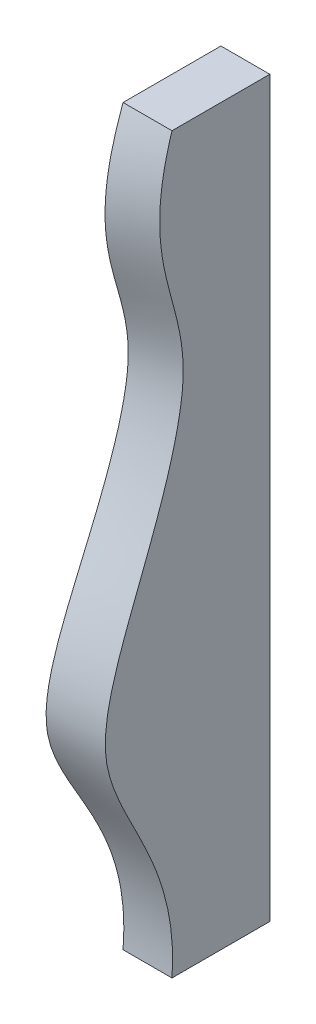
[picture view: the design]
ISO-10303-21;
HEADER;
FILE_DESCRIPTION(('STEP AP214'),'2;1');
FILE_NAME('part.step','',(''),(''),'','','');
FILE_SCHEMA(('AUTOMOTIVE_DESIGN { 1 0 10303 214 1 1 1 1 }'));
ENDSEC;
DATA;
#1=APPLICATION_CONTEXT('core data for automotive mechanical design processes');
#2=APPLICATION_PROTOCOL_DEFINITION('international standard','automotive_design',2000,#1);
#3=PRODUCT_CONTEXT('',#1,'mechanical');
#4=PRODUCT('Part','Part','',(#3));
#5=PRODUCT_RELATED_PRODUCT_CATEGORY('part','',(#4));
#6=PRODUCT_DEFINITION_FORMATION('','',#4);
#7=PRODUCT_DEFINITION_CONTEXT('part definition',#1,'design');
#8=PRODUCT_DEFINITION('design','',#6,#7);
#9=PRODUCT_DEFINITION_SHAPE('','',#8);
#10=(LENGTH_UNIT() NAMED_UNIT(*) SI_UNIT(.MILLI.,.METRE.));
#11=(NAMED_UNIT(*) PLANE_ANGLE_UNIT() SI_UNIT($,.RADIAN.));
#12=(NAMED_UNIT(*) SI_UNIT($,.STERADIAN.) SOLID_ANGLE_UNIT());
#13=UNCERTAINTY_MEASURE_WITH_UNIT(LENGTH_MEASURE(1.E-05),#10,'distance_accuracy_value','');
#14=(GEOMETRIC_REPRESENTATION_CONTEXT(3) GLOBAL_UNCERTAINTY_ASSIGNED_CONTEXT((#13)) GLOBAL_UNIT_ASSIGNED_CONTEXT((#10,
#11,#12)) REPRESENTATION_CONTEXT('',''));
#15=CARTESIAN_POINT('',(0.,0.,0.));
#16=DIRECTION('',(0.,0.,1.));
#17=DIRECTION('',(1.,0.,0.));
#18=AXIS2_PLACEMENT_3D('',#15,#16,#17);
#19=CARTESIAN_POINT('',(450.,375.,253.120113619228));
#20=DIRECTION('',(1.,0.,0.));
#21=DIRECTION('',(0.,0.,-1.));
#22=AXIS2_PLACEMENT_3D('',#19,#20,#21);
#23=PLANE('',#22);
#24=CARTESIAN_POINT('',(450.,375.,100.));
#25=CARTESIAN_POINT('',(450.,373.034518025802,100.617893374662));
#26=CARTESIAN_POINT('',(450.,371.063498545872,101.218327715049));
#27=CARTESIAN_POINT('',(450.,367.106931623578,102.38292904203));
#28=CARTESIAN_POINT('',(450.,365.121364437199,102.947028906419));
#29=CARTESIAN_POINT('',(450.,361.136834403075,104.036051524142));
#30=CARTESIAN_POINT('',(450.,359.137857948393,104.560924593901));
#31=CARTESIAN_POINT('',(450.,355.127662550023,105.568528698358));
#32=CARTESIAN_POINT('',(450.,353.116435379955,106.051227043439));
#33=CARTESIAN_POINT('',(450.,349.082885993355,106.971524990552));
#34=CARTESIAN_POINT('',(450.,347.060559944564,107.409107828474));
#35=CARTESIAN_POINT('',(450.,343.005968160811,108.236239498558));
#36=CARTESIAN_POINT('',(450.,340.973701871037,108.625785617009));
#37=CARTESIAN_POINT('',(450.,336.925879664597,109.349411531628));
#38=CARTESIAN_POINT('',(450.,334.910438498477,109.684131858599));
#39=CARTESIAN_POINT('',(450.,330.872251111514,110.301237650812));
#40=CARTESIAN_POINT('',(450.,328.849507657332,110.583641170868));
#41=CARTESIAN_POINT('',(450.,324.797929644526,111.093589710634));
#42=CARTESIAN_POINT('',(450.,322.769097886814,111.321156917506));
#43=CARTESIAN_POINT('',(450.,318.706578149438,111.719126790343));
#44=CARTESIAN_POINT('',(450.,316.672892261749,111.889550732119));
#45=CARTESIAN_POINT('',(450.,312.601936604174,112.171223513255));
#46=CARTESIAN_POINT('',(450.,310.564667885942,112.2824875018));
#47=CARTESIAN_POINT('',(450.,306.487835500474,112.444211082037));
#48=CARTESIAN_POINT('',(450.,304.44827200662,112.494674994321));
#49=CARTESIAN_POINT('',(450.,300.766861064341,112.529866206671));
#50=CARTESIAN_POINT('',(450.,299.125109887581,112.525504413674));
#51=CARTESIAN_POINT('',(450.,295.841944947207,112.476390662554));
#52=CARTESIAN_POINT('',(450.,294.20053127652,112.431632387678));
#53=CARTESIAN_POINT('',(450.,290.9191510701,112.301744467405));
#54=CARTESIAN_POINT('',(450.,289.279184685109,112.216611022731));
#55=CARTESIAN_POINT('',(450.,286.0017716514,112.006369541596));
#56=CARTESIAN_POINT('',(450.,284.364325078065,111.881260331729));
#57=CARTESIAN_POINT('',(450.,281.093002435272,111.591875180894));
#58=CARTESIAN_POINT('',(450.,279.459126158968,111.427601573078));
#59=CARTESIAN_POINT('',(450.,276.195965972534,111.061140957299));
#60=CARTESIAN_POINT('',(450.,274.566681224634,110.858961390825));
#61=CARTESIAN_POINT('',(450.,271.308912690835,110.417766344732));
#62=CARTESIAN_POINT('',(450.,269.680441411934,110.178658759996));
#63=CARTESIAN_POINT('',(450.,266.429067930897,109.66611714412));
#64=CARTESIAN_POINT('',(450.,264.806165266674,109.39268603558));
#65=CARTESIAN_POINT('',(450.,261.565975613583,108.814016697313));
#66=CARTESIAN_POINT('',(450.,259.948688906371,108.508776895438));
#67=CARTESIAN_POINT('',(450.,256.719693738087,107.869432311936));
#68=CARTESIAN_POINT('',(450.,255.107985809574,107.535324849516));
#69=CARTESIAN_POINT('',(450.,251.890031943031,106.84158166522));
#70=CARTESIAN_POINT('',(450.,250.283786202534,106.481945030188));
#71=CARTESIAN_POINT('',(450.,247.076559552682,105.740892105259));
#72=CARTESIAN_POINT('',(450.,245.475578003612,105.359478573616));
#73=CARTESIAN_POINT('',(450.,241.50463574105,104.389998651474));
#74=CARTESIAN_POINT('',(450.,239.137299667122,103.791213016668));
#75=CARTESIAN_POINT('',(450.,234.409562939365,102.56858360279));
#76=CARTESIAN_POINT('',(450.,232.049161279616,101.944743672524));
#77=CARTESIAN_POINT('',(450.,227.330957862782,100.687056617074));
#78=CARTESIAN_POINT('',(450.,224.97315619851,100.053209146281));
#79=CARTESIAN_POINT('',(450.,220.255645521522,98.7912632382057));
#80=CARTESIAN_POINT('',(450.,217.895936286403,98.1631656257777));
#81=CARTESIAN_POINT('',(450.,213.180890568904,96.9316236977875));
#82=CARTESIAN_POINT('',(450.,210.825579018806,96.3280848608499));
#83=CARTESIAN_POINT('',(450.,206.105641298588,95.1587191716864));
#84=CARTESIAN_POINT('',(450.,203.74101552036,94.5928907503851));
#85=CARTESIAN_POINT('',(450.,198.999701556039,93.5143370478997));
#86=CARTESIAN_POINT('',(450.,196.623014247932,93.0016079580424));
#87=CARTESIAN_POINT('',(450.,193.047444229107,92.2829932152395));
#88=CARTESIAN_POINT('',(450.,191.853625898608,92.0518328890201));
#89=CARTESIAN_POINT('',(450.,189.462562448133,91.6080101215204));
#90=CARTESIAN_POINT('',(450.,188.265317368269,91.395347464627));
#91=CARTESIAN_POINT('',(450.,185.438603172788,90.9175979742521));
#92=CARTESIAN_POINT('',(450.,183.807693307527,90.6609641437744));
#93=CARTESIAN_POINT('',(450.,180.539482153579,90.188070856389));
#94=CARTESIAN_POINT('',(450.,178.902178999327,89.9718242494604));
#95=CARTESIAN_POINT('',(450.,175.622465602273,89.582792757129));
#96=CARTESIAN_POINT('',(450.,173.980055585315,89.4100059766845));
#97=CARTESIAN_POINT('',(450.,170.691479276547,89.1103508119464));
#98=CARTESIAN_POINT('',(450.,169.045314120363,88.9834700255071));
#99=CARTESIAN_POINT('',(450.,165.7506468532,88.7774420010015));
#100=CARTESIAN_POINT('',(450.,164.10214592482,88.698275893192));
#101=CARTESIAN_POINT('',(450.,160.804237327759,88.5888757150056));
#102=CARTESIAN_POINT('',(450.,159.154830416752,88.5586193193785));
#103=CARTESIAN_POINT('',(450.,156.67780275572,88.5503605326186));
#104=CARTESIAN_POINT('',(450.,155.850205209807,88.5538336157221));
#105=CARTESIAN_POINT('',(450.,154.195150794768,88.5732733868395));
#106=CARTESIAN_POINT('',(450.,153.3676939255,88.5892400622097));
#107=CARTESIAN_POINT('',(450.,151.71303295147,88.6336548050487));
#108=CARTESIAN_POINT('',(450.,150.885828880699,88.6621041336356));
#109=CARTESIAN_POINT('',(450.,149.231947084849,88.7315153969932));
#110=CARTESIAN_POINT('',(450.,148.405269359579,88.7724773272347));
#111=CARTESIAN_POINT('',(450.,146.752342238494,88.8663764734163));
#112=CARTESIAN_POINT('',(450.,145.926093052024,88.9193173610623));
#113=CARTESIAN_POINT('',(450.,144.274400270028,89.0364829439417));
#114=CARTESIAN_POINT('',(450.,143.448956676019,89.1007076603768));
#115=CARTESIAN_POINT('',(450.,140.973367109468,89.3094573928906));
#116=CARTESIAN_POINT('',(450.,139.32455581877,89.4700233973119));
#117=CARTESIAN_POINT('',(450.,136.030767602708,89.8296137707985));
#118=CARTESIAN_POINT('',(450.,134.385791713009,90.0286475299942));
#119=CARTESIAN_POINT('',(450.,131.921842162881,90.353227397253));
#120=CARTESIAN_POINT('',(450.,131.101130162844,90.4657560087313));
#121=CARTESIAN_POINT('',(450.,129.46087288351,90.6990804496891));
#122=CARTESIAN_POINT('',(450.,128.641327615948,90.8198763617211));
#123=CARTESIAN_POINT('',(450.,126.487607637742,91.147902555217));
#124=CARTESIAN_POINT('',(450.,125.154422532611,91.3616516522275));
#125=CARTESIAN_POINT('',(450.,122.491297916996,91.8085097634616));
#126=CARTESIAN_POINT('',(450.,121.161358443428,92.0416189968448));
#127=CARTESIAN_POINT('',(450.,118.504649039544,92.5258118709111));
#128=CARTESIAN_POINT('',(450.,117.177879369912,92.7768969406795));
#129=CARTESIAN_POINT('',(450.,114.527649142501,93.2958707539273));
#130=CARTESIAN_POINT('',(450.,113.204188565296,93.5637593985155));
#131=CARTESIAN_POINT('',(450.,109.238311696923,94.3911977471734));
#132=CARTESIAN_POINT('',(450.,106.600813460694,94.974443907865));
#133=CARTESIAN_POINT('',(450.,101.338948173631,96.1967655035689));
#134=CARTESIAN_POINT('',(450.,98.7145807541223,96.8358393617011));
#135=CARTESIAN_POINT('',(450.,93.4750061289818,98.1644316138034));
#136=CARTESIAN_POINT('',(450.,90.8598154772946,98.8540151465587));
#137=CARTESIAN_POINT('',(450.,85.6414988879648,100.277365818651));
#138=CARTESIAN_POINT('',(450.,83.0383730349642,101.011133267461));
#139=CARTESIAN_POINT('',(450.,77.8401683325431,102.518956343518));
#140=CARTESIAN_POINT('',(450.,75.2451043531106,103.293063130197));
#141=CARTESIAN_POINT('',(450.,70.0657152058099,104.876319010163));
#142=CARTESIAN_POINT('',(450.,67.4813900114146,105.68546801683));
#143=CARTESIAN_POINT('',(450.,62.3209633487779,107.335422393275));
#144=CARTESIAN_POINT('',(450.,59.7448685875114,108.176248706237));
#145=CARTESIAN_POINT('',(450.,54.6018401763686,109.8854300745));
#146=CARTESIAN_POINT('',(450.,52.0349065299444,110.753785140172));
#147=CARTESIAN_POINT('',(450.,46.9102618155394,112.514359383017));
#148=CARTESIAN_POINT('',(450.,44.3525478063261,113.406570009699));
#149=CARTESIAN_POINT('',(450.,39.2445395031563,115.21200108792));
#150=CARTESIAN_POINT('',(450.,36.6942452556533,116.125221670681));
#151=CARTESIAN_POINT('',(450.,28.9927594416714,118.913724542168));
#152=CARTESIAN_POINT('',(450.,23.8516461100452,120.81684708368));
#153=CARTESIAN_POINT('',(450.,16.1571884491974,123.707385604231));
#154=CARTESIAN_POINT('',(450.,13.5968215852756,124.676261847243));
#155=CARTESIAN_POINT('',(450.,8.47962364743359,126.623321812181));
#156=CARTESIAN_POINT('',(450.,5.92279257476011,127.601505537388));
#157=CARTESIAN_POINT('',(450.,0.813723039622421,129.563215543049));
#158=CARTESIAN_POINT('',(450.,-1.73851748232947,130.54673647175));
#159=CARTESIAN_POINT('',(450.,-6.84186725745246,132.516709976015));
#160=CARTESIAN_POINT('',(450.,-9.392976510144,133.50316255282));
#161=CARTESIAN_POINT('',(450.,-14.4939994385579,135.474932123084));
#162=CARTESIAN_POINT('',(450.,-17.0439129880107,136.460249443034));
#163=CARTESIAN_POINT('',(450.,-22.1454321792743,138.42649349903));
#164=CARTESIAN_POINT('',(450.,-24.6970378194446,139.407420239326));
#165=CARTESIAN_POINT('',(450.,-29.8029132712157,141.360459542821));
#166=CARTESIAN_POINT('',(450.,-32.3571822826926,142.33257419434));
#167=CARTESIAN_POINT('',(450.,-37.4707422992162,144.263569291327));
#168=CARTESIAN_POINT('',(450.,-40.0300333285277,145.222449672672));
#169=CARTESIAN_POINT('',(450.,-45.1560846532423,147.121914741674));
#170=CARTESIAN_POINT('',(450.,-47.722846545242,148.062495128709));
#171=CARTESIAN_POINT('',(450.,-52.8652254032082,149.919094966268));
#172=CARTESIAN_POINT('',(450.,-55.4408422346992,150.835114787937));
#173=CARTESIAN_POINT('',(450.,-59.6540324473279,152.304591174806));
#174=CARTESIAN_POINT('',(450.,-61.2883027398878,152.867516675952));
#175=CARTESIAN_POINT('',(450.,-64.5620855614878,153.978834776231));
#176=CARTESIAN_POINT('',(450.,-66.201598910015,154.527224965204));
#177=CARTESIAN_POINT('',(450.,-69.4863474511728,155.607233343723));
#178=CARTESIAN_POINT('',(450.,-71.1315832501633,156.13884969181));
#179=CARTESIAN_POINT('',(450.,-74.4283278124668,157.182853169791));
#180=CARTESIAN_POINT('',(450.,-76.0798371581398,157.69523846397));
#181=CARTESIAN_POINT('',(450.,-79.3897557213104,158.698082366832));
#182=CARTESIAN_POINT('',(450.,-81.0481658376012,159.188538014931));
#183=CARTESIAN_POINT('',(450.,-84.3726006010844,160.144551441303));
#184=CARTESIAN_POINT('',(450.,-86.0386270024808,160.610103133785));
#185=CARTESIAN_POINT('',(450.,-89.3672350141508,161.509817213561));
#186=CARTESIAN_POINT('',(450.,-91.0297655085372,161.944168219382));
#187=CARTESIAN_POINT('',(450.,-94.3629556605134,162.781258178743));
#188=CARTESIAN_POINT('',(450.,-96.0336160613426,163.183994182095));
#189=CARTESIAN_POINT('',(450.,-99.3829859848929,163.95372299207));
#190=CARTESIAN_POINT('',(450.,-101.061694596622,164.320719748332));
#191=CARTESIAN_POINT('',(450.,-104.427153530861,165.014502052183));
#192=CARTESIAN_POINT('',(450.,-106.113902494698,165.341294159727));
#193=CARTESIAN_POINT('',(450.,-109.49549998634,165.949833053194));
#194=CARTESIAN_POINT('',(450.,-111.190348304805,166.231580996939));
#195=CARTESIAN_POINT('',(450.,-114.588323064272,166.744809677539));
#196=CARTESIAN_POINT('',(450.,-116.291452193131,166.976272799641));
#197=CARTESIAN_POINT('',(450.,-119.218456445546,167.325141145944));
#198=CARTESIAN_POINT('',(450.,-120.440704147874,167.456256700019));
#199=CARTESIAN_POINT('',(450.,-122.88831835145,167.687582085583));
#200=CARTESIAN_POINT('',(450.,-124.113685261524,167.787787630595));
#201=CARTESIAN_POINT('',(450.,-126.566468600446,167.954985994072));
#202=CARTESIAN_POINT('',(450.,-127.793884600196,168.021985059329));
#203=CARTESIAN_POINT('',(450.,-130.249711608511,168.120481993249));
#204=CARTESIAN_POINT('',(450.,-131.478122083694,168.1519929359));
#205=CARTESIAN_POINT('',(450.,-133.934864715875,168.177264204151));
#206=CARTESIAN_POINT('',(450.,-135.163196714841,168.171039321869));
#207=CARTESIAN_POINT('',(450.,-137.618754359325,168.11864771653));
#208=CARTESIAN_POINT('',(450.,-138.84598020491,168.072490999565));
#209=CARTESIAN_POINT('',(450.,-140.683182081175,167.971830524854));
#210=CARTESIAN_POINT('',(450.,-141.294055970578,167.933121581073));
#211=CARTESIAN_POINT('',(450.,-142.515038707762,167.845022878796));
#212=CARTESIAN_POINT('',(450.,-143.125147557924,167.795633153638));
#213=CARTESIAN_POINT('',(450.,-144.344540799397,167.685888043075));
#214=CARTESIAN_POINT('',(450.,-144.953824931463,167.625529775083));
#215=CARTESIAN_POINT('',(450.,-146.171215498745,167.493964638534));
#216=CARTESIAN_POINT('',(450.,-146.779321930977,167.422757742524));
#217=CARTESIAN_POINT('',(450.,-148.601930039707,167.193167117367));
#218=CARTESIAN_POINT('',(450.,-149.814455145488,167.018837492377));
#219=CARTESIAN_POINT('',(450.,-152.233189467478,166.629777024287));
#220=CARTESIAN_POINT('',(450.,-153.43939753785,166.415039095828));
#221=CARTESIAN_POINT('',(450.,-155.243113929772,166.064676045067));
#222=CARTESIAN_POINT('',(450.,-155.843403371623,165.943182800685));
#223=CARTESIAN_POINT('',(450.,-157.042076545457,165.69114294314));
#224=CARTESIAN_POINT('',(450.,-157.640460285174,165.560596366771));
#225=CARTESIAN_POINT('',(450.,-159.4319845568,165.155946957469));
#226=CARTESIAN_POINT('',(450.,-160.622176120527,164.868702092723));
#227=CARTESIAN_POINT('',(450.,-163.09637575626,164.235411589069));
#228=CARTESIAN_POINT('',(450.,-164.379630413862,163.886431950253));
#229=CARTESIAN_POINT('',(450.,-166.936033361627,163.153118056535));
#230=CARTESIAN_POINT('',(450.,-168.209181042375,162.768781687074));
#231=CARTESIAN_POINT('',(450.,-172.013585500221,161.567468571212));
#232=CARTESIAN_POINT('',(450.,-174.529674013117,160.702221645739));
#233=CARTESIAN_POINT('',(450.,-179.526936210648,158.866721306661));
#234=CARTESIAN_POINT('',(450.,-182.008052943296,157.896314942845));
#235=CARTESIAN_POINT('',(450.,-186.940912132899,155.872799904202));
#236=CARTESIAN_POINT('',(450.,-189.392599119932,154.819556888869));
#237=CARTESIAN_POINT('',(450.,-194.271291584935,152.651277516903));
#238=CARTESIAN_POINT('',(450.,-196.698269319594,151.536179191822));
#239=CARTESIAN_POINT('',(450.,-201.531653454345,149.263514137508));
#240=CARTESIAN_POINT('',(450.,-203.938063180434,148.10595444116));
#241=CARTESIAN_POINT('',(450.,-208.778520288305,145.744228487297));
#242=CARTESIAN_POINT('',(450.,-211.212343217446,144.539604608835));
#243=CARTESIAN_POINT('',(450.,-216.070097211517,142.119157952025));
#244=CARTESIAN_POINT('',(450.,-218.49403738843,140.903353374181));
#245=CARTESIAN_POINT('',(450.,-223.339509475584,138.47314369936));
#246=CARTESIAN_POINT('',(450.,-225.761041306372,137.258738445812));
#247=CARTESIAN_POINT('',(450.,-230.608479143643,134.842528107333));
#248=CARTESIAN_POINT('',(450.,-233.034381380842,133.64071548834));
#249=CARTESIAN_POINT('',(450.,-237.896771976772,131.25973662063));
#250=CARTESIAN_POINT('',(450.,-240.333258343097,130.080566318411));
#251=CARTESIAN_POINT('',(450.,-245.222540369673,127.753971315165));
#252=CARTESIAN_POINT('',(450.,-247.675341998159,126.606559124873));
#253=CARTESIAN_POINT('',(450.,-253.090046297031,124.12878248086));
#254=CARTESIAN_POINT('',(450.,-256.056108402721,122.80745990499));
#255=CARTESIAN_POINT('',(450.,-262.02202463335,120.238007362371));
#256=CARTESIAN_POINT('',(450.,-265.021898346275,118.989922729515));
#257=CARTESIAN_POINT('',(450.,-271.057210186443,116.581044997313));
#258=CARTESIAN_POINT('',(450.,-274.092653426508,115.420264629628));
#259=CARTESIAN_POINT('',(450.,-278.673049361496,113.753939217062));
#260=CARTESIAN_POINT('',(450.,-280.20444416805,113.210952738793));
#261=CARTESIAN_POINT('',(450.,-283.276312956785,112.151331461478));
#262=CARTESIAN_POINT('',(450.,-284.816786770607,111.634696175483));
#263=CARTESIAN_POINT('',(450.,-287.907160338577,110.628980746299));
#264=CARTESIAN_POINT('',(450.,-289.457062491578,110.139907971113));
#265=CARTESIAN_POINT('',(450.,-292.56568207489,109.190722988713));
#266=CARTESIAN_POINT('',(450.,-294.124399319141,108.730610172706));
#267=CARTESIAN_POINT('',(450.,-297.237191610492,107.844256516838));
#268=CARTESIAN_POINT('',(450.,-298.791194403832,107.417762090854));
#269=CARTESIAN_POINT('',(450.,-301.907254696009,106.595414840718));
#270=CARTESIAN_POINT('',(450.,-303.469312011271,106.199561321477));
#271=CARTESIAN_POINT('',(450.,-306.6015461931,105.439307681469));
#272=CARTESIAN_POINT('',(450.,-308.171725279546,105.074916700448));
#273=CARTESIAN_POINT('',(450.,-311.319221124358,104.378553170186));
#274=CARTESIAN_POINT('',(450.,-312.896537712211,104.046579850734));
#275=CARTESIAN_POINT('',(450.,-316.05752532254,103.415813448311));
#276=CARTESIAN_POINT('',(450.,-317.641195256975,103.117014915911));
#277=CARTESIAN_POINT('',(450.,-320.814491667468,102.553149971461));
#278=CARTESIAN_POINT('',(450.,-322.404117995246,102.288082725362));
#279=CARTESIAN_POINT('',(450.,-325.588001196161,101.792274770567));
#280=CARTESIAN_POINT('',(450.,-327.182255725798,101.561519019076));
#281=CARTESIAN_POINT('',(450.,-330.375348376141,101.134579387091));
#282=CARTESIAN_POINT('',(450.,-331.974186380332,100.938394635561));
#283=CARTESIAN_POINT('',(450.,-335.174747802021,100.580967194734));
#284=CARTESIAN_POINT('',(450.,-336.776468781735,100.419702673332));
#285=CARTESIAN_POINT('',(450.,-339.983003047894,100.132116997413));
#286=CARTESIAN_POINT('',(450.,-341.587816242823,100.005794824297));
#287=CARTESIAN_POINT('',(450.,-344.515288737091,99.8074111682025));
#288=CARTESIAN_POINT('',(450.,-345.83756850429,99.7297016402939));
#289=CARTESIAN_POINT('',(450.,-348.483037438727,99.5979494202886));
#290=CARTESIAN_POINT('',(450.,-349.806226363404,99.543901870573));
#291=CARTESIAN_POINT('',(450.,-352.453184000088,99.4593816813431));
#292=CARTESIAN_POINT('',(450.,-353.776952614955,99.4289059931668));
#293=CARTESIAN_POINT('',(450.,-356.424744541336,99.3914001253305));
#294=CARTESIAN_POINT('',(450.,-357.748767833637,99.3843685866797));
#295=CARTESIAN_POINT('',(450.,-360.401080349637,99.3936025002));
#296=CARTESIAN_POINT('',(450.,-361.729369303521,99.4099445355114));
#297=CARTESIAN_POINT('',(450.,-364.385534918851,99.4658640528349));
#298=CARTESIAN_POINT('',(450.,-365.713411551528,99.505442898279));
#299=CARTESIAN_POINT('',(450.,-368.368416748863,99.6076070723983));
#300=CARTESIAN_POINT('',(450.,-369.695545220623,99.6701948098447));
#301=CARTESIAN_POINT('',(450.,-372.34872359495,99.8181098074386));
#302=CARTESIAN_POINT('',(450.,-373.67477331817,99.9034402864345));
#303=CARTESIAN_POINT('',(450.,-375.,100.));
#304=B_SPLINE_CURVE_WITH_KNOTS('',3,(#24,#25,#26,#27,#28,#29,#30,#31,#32,#33,#34,#35,#36,#37,
#38,#39,#40,#41,#42,#43,#44,#45,#46,#47,#48,#49,#50,#51,#52,#53,#54,#55,#56,#57,#58,#59,#60,#61,
#62,#63,#64,#65,#66,#67,#68,#69,#70,#71,#72,#73,#74,#75,#76,#77,#78,#79,#80,#81,#82,#83,#84,#85,
#86,#87,#88,#89,#90,#91,#92,#93,#94,#95,#96,#97,#98,#99,#100,#101,#102,#103,#104,#105,#106,#107,
#108,#109,#110,#111,#112,#113,#114,#115,#116,#117,#118,#119,#120,#121,#122,#123,#124,#125,#126,
#127,#128,#129,#130,#131,#132,#133,#134,#135,#136,#137,#138,#139,#140,#141,#142,#143,#144,#145,
#146,#147,#148,#149,#150,#151,#152,#153,#154,#155,#156,#157,#158,#159,#160,#161,#162,#163,#164,
#165,#166,#167,#168,#169,#170,#171,#172,#173,#174,#175,#176,#177,#178,#179,#180,#181,#182,#183,
#184,#185,#186,#187,#188,#189,#190,#191,#192,#193,#194,#195,#196,#197,#198,#199,#200,#201,#202,
#203,#204,#205,#206,#207,#208,#209,#210,#211,#212,#213,#214,#215,#216,#217,#218,#219,#220,#221,
#222,#223,#224,#225,#226,#227,#228,#229,#230,#231,#232,#233,#234,#235,#236,#237,#238,#239,#240,
#241,#242,#243,#244,#245,#246,#247,#248,#249,#250,#251,#252,#253,#254,#255,#256,#257,#258,#259,
#260,#261,#262,#263,#264,#265,#266,#267,#268,#269,#270,#271,#272,#273,#274,#275,#276,#277,#278,
#279,#280,#281,#282,#283,#284,#285,#286,#287,#288,#289,#290,#291,#292,#293,#294,#295,#296,#297,
#298,#299,#300,#301,#302,#303),.UNSPECIFIED.,.F.,.F.,(4,2,2,2,2,2,2,2,2,2,2,2,2,2,2,2,2,2,2,2,2,
2,2,2,2,2,2,2,2,2,2,2,2,2,2,2,2,2,2,2,2,2,2,2,2,2,2,2,2,2,2,2,2,2,2,2,2,2,2,2,2,2,2,2,2,2,2,2,2,
2,2,2,2,2,2,2,2,2,2,2,2,2,2,2,2,2,2,2,2,2,2,2,2,2,2,2,2,2,2,2,2,2,2,2,2,2,2,2,2,2,2,2,2,2,2,2,2,
2,2,2,2,2,2,2,2,2,2,2,2,2,2,2,2,2,2,2,2,2,2,4),(0.,6.18094268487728,12.3729942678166,
18.5727600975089,24.7772895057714,30.9841161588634,37.1912932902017,43.3197838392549,
49.4461554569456,55.5700441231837,61.691650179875,67.8116879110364,73.9312907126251,
78.856087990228,83.7816554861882,88.7076865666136,93.633862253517,98.5597445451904,
103.484660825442,108.422065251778,113.359049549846,118.296277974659,123.233965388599,
128.17182950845,133.109069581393,140.434485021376,147.758779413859,155.083327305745,
162.408909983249,169.702944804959,176.996675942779,184.289883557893,187.937735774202,
191.585545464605,196.537997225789,201.492022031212,206.445830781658,211.398300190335,
216.348809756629,221.297058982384,223.779795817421,226.262530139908,228.745515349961,
231.228499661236,233.712246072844,236.195997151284,241.165282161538,246.135781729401,
248.620917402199,251.10607789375,255.156547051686,259.207062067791,263.257899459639,
267.308713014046,275.411600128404,283.514258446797,291.627556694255,299.740911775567,
307.864819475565,315.988707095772,324.118063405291,332.247422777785,340.373906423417,
348.500440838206,364.94612760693,373.158783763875,381.371442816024,389.57699962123,
397.782559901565,405.983546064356,414.184524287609,422.383505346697,430.582526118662,
438.783450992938,446.984251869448,452.16970579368,457.356014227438,462.542890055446,
467.730259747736,472.918327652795,478.107657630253,483.262382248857,488.417587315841,
493.572222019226,498.726014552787,503.879674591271,509.035137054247,512.722571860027,
516.410517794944,520.097769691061,523.783662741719,527.468111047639,531.151636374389,
532.987856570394,534.824071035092,536.660768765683,538.497471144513,542.171674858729,
545.84652342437,547.683844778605,549.521158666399,553.19371495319,557.182738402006,
561.172000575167,569.150926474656,577.14161724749,585.145545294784,593.157642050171,
601.168417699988,609.315204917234,617.450496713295,625.577445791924,633.699217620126,
641.819521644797,649.942980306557,659.683324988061,669.429636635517,679.177366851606,
684.051595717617,688.925734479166,693.801170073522,698.676503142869,703.510598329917,
708.344583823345,713.179968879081,718.015239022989,722.849713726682,727.684068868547,
732.516298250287,737.348405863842,742.177483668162,747.006420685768,750.979900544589,
754.952564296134,758.92471415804,762.896633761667,766.881597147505,770.866794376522,
774.852408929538,778.838587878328),.UNSPECIFIED.);
#305=CARTESIAN_POINT('',(450.,375.,100.));
#306=VERTEX_POINT('',#305);
#307=CARTESIAN_POINT('',(450.,-375.,100.));
#308=VERTEX_POINT('',#307);
#309=EDGE_CURVE('E88',#306,#308,#304,.T.);
#310=ORIENTED_EDGE('',*,*,#309,.T.);
#311=DIRECTION('',(0.,0.,-1.));
#312=VECTOR('',#311,1.);
#313=CARTESIAN_POINT('',(450.,-375.,253.120113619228));
#314=LINE('',#313,#312);
#315=CARTESIAN_POINT('',(450.,-375.,0.));
#316=VERTEX_POINT('',#315);
#317=EDGE_CURVE('E50',#308,#316,#314,.T.);
#318=ORIENTED_EDGE('',*,*,#317,.T.);
#319=DIRECTION('',(0.,-1.,0.));
#320=VECTOR('',#319,1.);
#321=CARTESIAN_POINT('',(450.,375.,0.));
#322=LINE('',#321,#320);
#323=CARTESIAN_POINT('',(450.,375.,0.));
#324=VERTEX_POINT('',#323);
#325=EDGE_CURVE('E87',#324,#316,#322,.T.);
#326=ORIENTED_EDGE('',*,*,#325,.F.);
#327=DIRECTION('',(0.,0.,-1.));
#328=VECTOR('',#327,1.);
#329=CARTESIAN_POINT('',(450.,375.,253.120113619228));
#330=LINE('',#329,#328);
#331=EDGE_CURVE('E65',#306,#324,#330,.T.);
#332=ORIENTED_EDGE('',*,*,#331,.F.);
#333=EDGE_LOOP('',(#310,#318,#326,#332));
#334=FACE_BOUND('',#333,.T.);
#335=ADVANCED_FACE('F35',(#334),#23,.T.);
#336=CARTESIAN_POINT('',(0.,0.,0.));
#337=DIRECTION('',(0.,0.,-1.));
#338=DIRECTION('',(-1.,0.,0.));
#339=AXIS2_PLACEMENT_3D('',#336,#337,#338);
#340=PLANE('',#339);
#341=DIRECTION('',(1.,0.,0.));
#342=VECTOR('',#341,1.);
#343=CARTESIAN_POINT('',(-750.,-375.,0.));
#344=LINE('',#343,#342);
#345=CARTESIAN_POINT('',(400.,-375.,0.));
#346=VERTEX_POINT('',#345);
#347=EDGE_CURVE('E79',#346,#316,#344,.T.);
#348=ORIENTED_EDGE('',*,*,#347,.F.);
#349=DIRECTION('',(0.,1.,0.));
#350=VECTOR('',#349,1.);
#351=CARTESIAN_POINT('',(400.,375.,0.));
#352=LINE('',#351,#350);
#353=CARTESIAN_POINT('',(400.,375.,0.));
#354=VERTEX_POINT('',#353);
#355=EDGE_CURVE('E157',#346,#354,#352,.T.);
#356=ORIENTED_EDGE('',*,*,#355,.T.);
#357=DIRECTION('',(-1.,0.,0.));
#358=VECTOR('',#357,1.);
#359=CARTESIAN_POINT('',(-750.,375.,0.));
#360=LINE('',#359,#358);
#361=EDGE_CURVE('E93',#324,#354,#360,.T.);
#362=ORIENTED_EDGE('',*,*,#361,.F.);
#363=ORIENTED_EDGE('',*,*,#325,.T.);
#364=EDGE_LOOP('',(#348,#356,#362,#363));
#365=FACE_BOUND('',#364,.T.);
#366=ADVANCED_FACE('F91',(#365),#340,.T.);
#367=CARTESIAN_POINT('',(750.,-375.,100.));
#368=CARTESIAN_POINT('',(750.,-302.078506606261,100.));
#369=CARTESIAN_POINT('',(750.,-224.483786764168,100.));
#370=CARTESIAN_POINT('',(750.,-61.5160152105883,100.));
#371=CARTESIAN_POINT('',(750.,39.4445673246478,100.));
#372=CARTESIAN_POINT('',(750.,211.849847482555,100.));
#373=CARTESIAN_POINT('',(750.,298.882075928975,100.));
#374=CARTESIAN_POINT('',(750.,375.,100.));
#375=CARTESIAN_POINT('',(669.085175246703,-375.,100.));
#376=CARTESIAN_POINT('',(669.085175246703,-302.078506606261,100.));
#377=CARTESIAN_POINT('',(669.085175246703,-234.282472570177,121.198481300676));
#378=CARTESIAN_POINT('',(669.085175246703,-62.2283080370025,120.288550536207));
#379=CARTESIAN_POINT('',(669.085175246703,68.0647781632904,82.7868169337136));
#380=CARTESIAN_POINT('',(669.085175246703,240.312514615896,73.0426687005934));
#381=CARTESIAN_POINT('',(669.085175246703,298.882075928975,100.));
#382=CARTESIAN_POINT('',(669.085175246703,375.,100.));
#383=CARTESIAN_POINT('',(500.445116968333,-375.,100.));
#384=CARTESIAN_POINT('',(517.991528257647,-284.627602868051,95.5040591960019));
#385=CARTESIAN_POINT('',(530.038001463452,-221.673003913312,150.719602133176));
#386=CARTESIAN_POINT('',(473.74510655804,-71.7416270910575,167.060530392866));
#387=CARTESIAN_POINT('',(387.213321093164,45.6135081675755,91.591323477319));
#388=CARTESIAN_POINT('',(378.694107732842,207.638743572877,66.6461848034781));
#389=CARTESIAN_POINT('',(433.17831170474,253.396603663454,122.492891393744));
#390=CARTESIAN_POINT('',(500.445116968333,375.,100.));
#391=CARTESIAN_POINT('',(285.091607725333,-375.,100.));
#392=CARTESIAN_POINT('',(309.270321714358,-264.297524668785,86.4064578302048));
#393=CARTESIAN_POINT('',(325.856840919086,-200.08226970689,164.07204721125));
#394=CARTESIAN_POINT('',(247.47112957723,-80.9425320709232,234.992870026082));
#395=CARTESIAN_POINT('',(127.240382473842,2.40271344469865,186.756001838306));
#396=CARTESIAN_POINT('',(115.567806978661,152.518027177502,151.057444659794));
#397=CARTESIAN_POINT('',(191.428893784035,202.025100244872,189.039851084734));
#398=CARTESIAN_POINT('',(285.091607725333,375.,100.));
#399=CARTESIAN_POINT('',(47.4554331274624,-375.,100.));
#400=CARTESIAN_POINT('',(51.0669239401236,-278.639867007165,99.5141662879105));
#401=CARTESIAN_POINT('',(52.9210710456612,-231.452124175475,201.325948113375));
#402=CARTESIAN_POINT('',(3.18149891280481,-90.8615864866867,272.445475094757));
#403=CARTESIAN_POINT('',(-61.0346058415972,45.7948958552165,186.157760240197));
#404=CARTESIAN_POINT('',(-59.6612105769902,205.286893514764,133.941969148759));
#405=CARTESIAN_POINT('',(-11.8049718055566,220.40073671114,189.8209162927));
#406=CARTESIAN_POINT('',(47.4554331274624,375.,100.));
#407=CARTESIAN_POINT('',(-175.903454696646,-375.,100.));
#408=CARTESIAN_POINT('',(-199.823715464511,-320.588060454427,126.731848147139));
#409=CARTESIAN_POINT('',(-216.967937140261,-300.821135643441,242.921959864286));
#410=CARTESIAN_POINT('',(-184.265304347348,-55.1410097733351,206.147478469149));
#411=CARTESIAN_POINT('',(-119.865061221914,249.096629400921,-32.5779079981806));
#412=CARTESIAN_POINT('',(-104.641938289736,431.262460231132,-94.4845569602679));
#413=CARTESIAN_POINT('',(-136.623034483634,348.137040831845,60.785640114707));
#414=CARTESIAN_POINT('',(-175.903454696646,375.,100.));
#415=CARTESIAN_POINT('',(-355.235514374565,-375.,100.));
#416=CARTESIAN_POINT('',(-319.200833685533,-282.590755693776,58.2859511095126));
#417=CARTESIAN_POINT('',(-293.075279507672,-226.888141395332,104.97090627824));
#418=CARTESIAN_POINT('',(-324.119079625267,-68.6572837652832,122.102733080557));
#419=CARTESIAN_POINT('',(-398.972481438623,73.039345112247,53.3701087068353));
#420=CARTESIAN_POINT('',(-423.398679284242,233.384819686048,47.4380317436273));
#421=CARTESIAN_POINT('',(-392.720188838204,253.575952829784,124.952096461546));
#422=CARTESIAN_POINT('',(-355.235514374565,375.,100.));
#423=CARTESIAN_POINT('',(-536.684515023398,-375.,100.));
#424=CARTESIAN_POINT('',(-494.827225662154,-277.129657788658,52.0422385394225));
#425=CARTESIAN_POINT('',(-464.573647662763,-205.017596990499,67.039018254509));
#426=CARTESIAN_POINT('',(-506.334367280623,-72.2467511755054,96.5036749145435));
#427=CARTESIAN_POINT('',(-600.216684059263,9.35641022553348,95.9941925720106));
#428=CARTESIAN_POINT('',(-628.122542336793,166.946160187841,106.349064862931));
#429=CARTESIAN_POINT('',(-587.011939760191,237.095914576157,138.331902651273));
#430=CARTESIAN_POINT('',(-536.684515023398,375.,100.));
#431=CARTESIAN_POINT('',(-644.685568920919,-375.,100.));
#432=CARTESIAN_POINT('',(-644.685568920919,-302.078506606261,100.));
#433=CARTESIAN_POINT('',(-644.685568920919,-237.237234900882,127.59081546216));
#434=CARTESIAN_POINT('',(-644.685568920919,-62.4430976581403,126.406497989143));
#435=CARTESIAN_POINT('',(-644.685568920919,76.6951111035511,77.5962366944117));
#436=CARTESIAN_POINT('',(-644.685568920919,248.895340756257,64.9137717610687));
#437=CARTESIAN_POINT('',(-644.685568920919,298.882075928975,100.));
#438=CARTESIAN_POINT('',(-644.685568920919,375.,100.));
#439=CARTESIAN_POINT('',(-750.,-375.,100.));
#440=CARTESIAN_POINT('',(-750.,-302.078506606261,100.));
#441=CARTESIAN_POINT('',(-750.,-224.483786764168,100.));
#442=CARTESIAN_POINT('',(-750.,-61.5160152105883,100.));
#443=CARTESIAN_POINT('',(-750.,39.4445673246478,100.));
#444=CARTESIAN_POINT('',(-750.,211.849847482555,100.));
#445=CARTESIAN_POINT('',(-750.,298.882075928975,100.));
#446=CARTESIAN_POINT('',(-750.,375.,100.));
#447=B_SPLINE_SURFACE_WITH_KNOTS('',3,3,((#367,#368,#369,#370,#371,#372,#373,#374),(#375,#376,
#377,#378,#379,#380,#381,#382),(#383,#384,#385,#386,#387,#388,#389,#390),(#391,#392,#393,#394,
#395,#396,#397,#398),(#399,#400,#401,#402,#403,#404,#405,#406),(#407,#408,#409,#410,#411,#412,
#413,#414),(#415,#416,#417,#418,#419,#420,#421,#422),(#423,#424,#425,#426,#427,#428,#429,#430),
(#431,#432,#433,#434,#435,#436,#437,#438),(#439,#440,#441,#442,#443,#444,#445,#446)),
.UNSPECIFIED.,.F.,.F.,.F.,(4,1,1,1,1,1,1,4),(4,1,1,1,1,4),(0.,0.161829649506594,
0.33728011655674,0.430707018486,0.637101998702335,0.783997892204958,0.789371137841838,1.),(0.,
0.291685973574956,0.310378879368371,0.65187108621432,0.695528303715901,1.),.UNSPECIFIED.);
#448=CARTESIAN_POINT('',(400.,-375.,100.));
#449=CARTESIAN_POINT('',(400.,-372.94881345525,99.8239564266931));
#450=CARTESIAN_POINT('',(400.,-370.895227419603,99.6754419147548));
#451=CARTESIAN_POINT('',(400.,-366.784512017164,99.4347576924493));
#452=CARTESIAN_POINT('',(400.,-364.727382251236,99.342594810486));
#453=CARTESIAN_POINT('',(400.,-360.611291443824,99.2159425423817));
#454=CARTESIAN_POINT('',(400.,-358.552330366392,99.1814543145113));
#455=CARTESIAN_POINT('',(400.,-354.434320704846,99.1712200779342));
#456=CARTESIAN_POINT('',(400.,-352.375272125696,99.1954721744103));
#457=CARTESIAN_POINT('',(400.,-348.258825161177,99.3035630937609));
#458=CARTESIAN_POINT('',(400.,-346.201426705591,99.3873992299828));
#459=CARTESIAN_POINT('',(400.,-342.090018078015,99.615244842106));
#460=CARTESIAN_POINT('',(400.,-340.03600780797,99.7592525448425));
#461=CARTESIAN_POINT('',(400.,-335.987523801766,100.103129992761));
#462=CARTESIAN_POINT('',(400.,-333.992915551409,100.301417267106));
#463=CARTESIAN_POINT('',(400.,-330.010371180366,100.755302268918));
#464=CARTESIAN_POINT('',(400.,-328.022434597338,101.010895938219));
#465=CARTESIAN_POINT('',(400.,-324.054854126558,101.579105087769));
#466=CARTESIAN_POINT('',(400.,-322.075209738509,101.891717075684));
#467=CARTESIAN_POINT('',(400.,-318.125779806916,102.573377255));
#468=CARTESIAN_POINT('',(400.,-316.155993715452,102.942422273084));
#469=CARTESIAN_POINT('',(400.,-312.227797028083,103.73605396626));
#470=CARTESIAN_POINT('',(400.,-310.269385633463,104.160636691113));
#471=CARTESIAN_POINT('',(400.,-306.365390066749,105.064135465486));
#472=CARTESIAN_POINT('',(400.,-304.419804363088,105.543044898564));
#473=CARTESIAN_POINT('',(400.,-300.779441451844,106.491985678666));
#474=CARTESIAN_POINT('',(400.,-299.083077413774,106.955946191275));
#475=CARTESIAN_POINT('',(400.,-295.701633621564,107.923470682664));
#476=CARTESIAN_POINT('',(400.,-294.016554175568,108.42703573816));
#477=CARTESIAN_POINT('',(400.,-290.657944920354,109.472550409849));
#478=CARTESIAN_POINT('',(400.,-288.984417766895,110.014508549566));
#479=CARTESIAN_POINT('',(400.,-285.64973418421,111.135244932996));
#480=CARTESIAN_POINT('',(400.,-283.988577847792,111.714023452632));
#481=CARTESIAN_POINT('',(400.,-280.67844839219,112.906980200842));
#482=CARTESIAN_POINT('',(400.,-279.029479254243,113.521169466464));
#483=CARTESIAN_POINT('',(400.,-275.744420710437,114.78305618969));
#484=CARTESIAN_POINT('',(400.,-274.108331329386,115.430753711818));
#485=CARTESIAN_POINT('',(400.,-270.849124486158,116.757789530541));
#486=CARTESIAN_POINT('',(400.,-269.226006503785,117.437126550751));
#487=CARTESIAN_POINT('',(400.,-265.992512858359,118.825538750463));
#488=CARTESIAN_POINT('',(400.,-264.382137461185,119.534614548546));
#489=CARTESIAN_POINT('',(400.,-261.145199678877,120.993382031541));
#490=CARTESIAN_POINT('',(400.,-259.518862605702,121.743573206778));
#491=CARTESIAN_POINT('',(400.,-256.278634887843,123.27042412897));
#492=CARTESIAN_POINT('',(400.,-254.664744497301,124.047084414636));
#493=CARTESIAN_POINT('',(400.,-251.449242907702,125.624322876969));
#494=CARTESIAN_POINT('',(400.,-249.847628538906,126.424894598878));
#495=CARTESIAN_POINT('',(400.,-246.655463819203,128.047735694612));
#496=CARTESIAN_POINT('',(400.,-245.064913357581,128.87000485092));
#497=CARTESIAN_POINT('',(400.,-241.894249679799,130.533567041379));
#498=CARTESIAN_POINT('',(400.,-240.31413425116,131.374855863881));
#499=CARTESIAN_POINT('',(400.,-237.162872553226,133.074036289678));
#500=CARTESIAN_POINT('',(400.,-235.591726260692,133.93192784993));
#501=CARTESIAN_POINT('',(400.,-232.458106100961,135.661072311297));
#502=CARTESIAN_POINT('',(400.,-230.895627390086,136.532316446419));
#503=CARTESIAN_POINT('',(400.,-227.776903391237,138.285875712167));
#504=CARTESIAN_POINT('',(400.,-226.220658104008,139.168190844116));
#505=CARTESIAN_POINT('',(400.,-222.60295899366,141.231765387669));
#506=CARTESIAN_POINT('',(400.,-220.54327718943,142.416126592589));
#507=CARTESIAN_POINT('',(400.,-216.4285415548,144.791422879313));
#508=CARTESIAN_POINT('',(400.,-214.373486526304,145.982355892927));
#509=CARTESIAN_POINT('',(400.,-210.262159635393,148.363384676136));
#510=CARTESIAN_POINT('',(400.,-208.205887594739,149.553480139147));
#511=CARTESIAN_POINT('',(400.,-204.085784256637,151.924551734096));
#512=CARTESIAN_POINT('',(400.,-202.021948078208,153.105519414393));
#513=CARTESIAN_POINT('',(400.,-197.879739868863,155.448954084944));
#514=CARTESIAN_POINT('',(400.,-195.801350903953,156.611391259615));
#515=CARTESIAN_POINT('',(400.,-191.622262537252,158.907017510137));
#516=CARTESIAN_POINT('',(400.,-189.521523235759,160.040134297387));
#517=CARTESIAN_POINT('',(400.,-185.357610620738,162.228582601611));
#518=CARTESIAN_POINT('',(400.,-183.295126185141,163.285218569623));
#519=CARTESIAN_POINT('',(400.,-179.140802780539,165.341898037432));
#520=CARTESIAN_POINT('',(400.,-177.048951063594,166.341915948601));
#521=CARTESIAN_POINT('',(400.,-172.834458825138,168.267009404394));
#522=CARTESIAN_POINT('',(400.,-170.711866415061,169.192189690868));
#523=CARTESIAN_POINT('',(400.,-166.433831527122,170.948319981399));
#524=CARTESIAN_POINT('',(400.,-164.278485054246,171.77950104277));
#525=CARTESIAN_POINT('',(400.,-161.018202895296,172.94099827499));
#526=CARTESIAN_POINT('',(400.,-159.928239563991,173.313550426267));
#527=CARTESIAN_POINT('',(400.,-157.73832586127,174.02796562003));
#528=CARTESIAN_POINT('',(400.,-156.638376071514,174.369830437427));
#529=CARTESIAN_POINT('',(400.,-154.429850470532,175.019854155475));
#530=CARTESIAN_POINT('',(400.,-153.321285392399,175.328049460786));
#531=CARTESIAN_POINT('',(400.,-151.094605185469,175.907639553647));
#532=CARTESIAN_POINT('',(400.,-149.976490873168,176.179037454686));
#533=CARTESIAN_POINT('',(400.,-148.298328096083,176.554730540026));
#534=CARTESIAN_POINT('',(400.,-147.741643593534,176.674191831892));
#535=CARTESIAN_POINT('',(400.,-146.626187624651,176.90291237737));
#536=CARTESIAN_POINT('',(400.,-146.067416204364,177.012171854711));
#537=CARTESIAN_POINT('',(400.,-144.947530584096,177.220226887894));
#538=CARTESIAN_POINT('',(400.,-144.386415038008,177.319015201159));
#539=CARTESIAN_POINT('',(400.,-143.262370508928,177.50569332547));
#540=CARTESIAN_POINT('',(400.,-142.699441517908,177.593583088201));
#541=CARTESIAN_POINT('',(400.,-141.571712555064,177.758533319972));
#542=CARTESIAN_POINT('',(400.,-141.00691179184,177.835588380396));
#543=CARTESIAN_POINT('',(400.,-139.875959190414,177.978983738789));
#544=CARTESIAN_POINT('',(400.,-139.309807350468,178.04532402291));
#545=CARTESIAN_POINT('',(400.,-137.609226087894,178.228548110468));
#546=CARTESIAN_POINT('',(400.,-136.47305113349,178.329579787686));
#547=CARTESIAN_POINT('',(400.,-134.19772420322,178.490875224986));
#548=CARTESIAN_POINT('',(400.,-133.05857188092,178.55113400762));
#549=CARTESIAN_POINT('',(400.,-130.779235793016,178.632584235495));
#550=CARTESIAN_POINT('',(400.,-129.639052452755,178.653787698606));
#551=CARTESIAN_POINT('',(400.,-127.345696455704,178.659078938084));
#552=CARTESIAN_POINT('',(400.,-126.192523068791,178.642743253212));
#553=CARTESIAN_POINT('',(400.,-123.887452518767,178.574146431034));
#554=CARTESIAN_POINT('',(400.,-122.735555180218,178.521891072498));
#555=CARTESIAN_POINT('',(400.,-120.433816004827,178.383578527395));
#556=CARTESIAN_POINT('',(400.,-119.283974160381,178.297521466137));
#557=CARTESIAN_POINT('',(400.,-116.987125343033,178.093735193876));
#558=CARTESIAN_POINT('',(400.,-115.840118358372,177.976006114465));
#559=CARTESIAN_POINT('',(400.,-113.549712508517,177.711000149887));
#560=CARTESIAN_POINT('',(400.,-112.406313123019,177.563727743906));
#561=CARTESIAN_POINT('',(400.,-110.123920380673,177.241743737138));
#562=CARTESIAN_POINT('',(400.,-108.984925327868,177.067044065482));
#563=CARTESIAN_POINT('',(400.,-105.683585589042,176.522715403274));
#564=CARTESIAN_POINT('',(400.,-103.526708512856,176.119610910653));
#565=CARTESIAN_POINT('',(400.,-99.2292460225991,175.233660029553));
#566=CARTESIAN_POINT('',(400.,-97.0886634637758,174.750799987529));
#567=CARTESIAN_POINT('',(400.,-92.8232735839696,173.716530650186));
#568=CARTESIAN_POINT('',(400.,-90.6984731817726,173.165092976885));
#569=CARTESIAN_POINT('',(400.,-86.4650734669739,172.003903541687));
#570=CARTESIAN_POINT('',(400.,-84.3564733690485,171.394154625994));
#571=CARTESIAN_POINT('',(400.,-80.1484581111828,170.123326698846));
#572=CARTESIAN_POINT('',(400.,-78.049084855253,169.462109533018));
#573=CARTESIAN_POINT('',(400.,-73.8641081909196,168.09752606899));
#574=CARTESIAN_POINT('',(400.,-71.7785049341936,167.394159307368));
#575=CARTESIAN_POINT('',(400.,-67.6139381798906,165.949998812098));
#576=CARTESIAN_POINT('',(400.,-65.5350084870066,165.20910789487));
#577=CARTESIAN_POINT('',(400.,-61.3880408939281,163.697551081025));
#578=CARTESIAN_POINT('',(400.,-59.320002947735,162.926885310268));
#579=CARTESIAN_POINT('',(400.,-55.1901733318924,161.359709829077));
#580=CARTESIAN_POINT('',(400.,-53.1283959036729,160.563162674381));
#581=CARTESIAN_POINT('',(400.,-49.0127817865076,158.949849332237));
#582=CARTESIAN_POINT('',(400.,-46.9589451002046,158.133083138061));
#583=CARTESIAN_POINT('',(400.,-42.8584336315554,156.483558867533));
#584=CARTESIAN_POINT('',(400.,-40.8117568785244,155.650805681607));
#585=CARTESIAN_POINT('',(400.,-36.7236266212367,153.972598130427));
#586=CARTESIAN_POINT('',(400.,-34.6821731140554,153.127143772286));
#587=CARTESIAN_POINT('',(400.,-30.5729076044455,151.414041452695));
#588=CARTESIAN_POINT('',(400.,-28.50515531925,150.546250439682));
#589=CARTESIAN_POINT('',(400.,-24.3725445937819,148.803813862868));
#590=CARTESIAN_POINT('',(400.,-22.3076861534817,147.929168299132));
#591=CARTESIAN_POINT('',(400.,-18.1842358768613,146.177640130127));
#592=CARTESIAN_POINT('',(400.,-16.1256401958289,145.300766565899));
#593=CARTESIAN_POINT('',(400.,-12.0091588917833,143.545357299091));
#594=CARTESIAN_POINT('',(400.,-9.95127326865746,142.666821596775));
#595=CARTESIAN_POINT('',(400.,-5.83856863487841,140.911806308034));
#596=CARTESIAN_POINT('',(400.,-3.78375006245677,140.035325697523));
#597=CARTESIAN_POINT('',(400.,0.327066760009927,138.285136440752));
#598=CARTESIAN_POINT('',(400.,2.38306501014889,137.411427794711));
#599=CARTESIAN_POINT('',(400.,8.54981236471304,134.799367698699));
#600=CARTESIAN_POINT('',(400.,12.6636298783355,133.068230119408));
#601=CARTESIAN_POINT('',(400.,20.9040082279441,129.641413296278));
#602=CARTESIAN_POINT('',(400.,25.0305629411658,127.945719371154));
#603=CARTESIAN_POINT('',(400.,33.3050972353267,124.603568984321));
#604=CARTESIAN_POINT('',(400.,37.4530828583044,122.957127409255));
#605=CARTESIAN_POINT('',(400.,43.9047206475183,120.4548093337));
#606=CARTESIAN_POINT('',(400.,46.199539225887,119.576149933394));
#607=CARTESIAN_POINT('',(400.,50.7987791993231,117.841013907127));
#608=CARTESIAN_POINT('',(400.,53.1032045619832,116.984547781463));
#609=CARTESIAN_POINT('',(400.,57.7222021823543,115.296850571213));
#610=CARTESIAN_POINT('',(400.,60.0367777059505,114.465628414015));
#611=CARTESIAN_POINT('',(400.,64.6766895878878,112.83165409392));
#612=CARTESIAN_POINT('',(400.,67.002028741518,112.028909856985));
#613=CARTESIAN_POINT('',(400.,71.6641642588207,110.455362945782));
#614=CARTESIAN_POINT('',(400.,74.0009633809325,109.684568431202));
#615=CARTESIAN_POINT('',(400.,78.6868249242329,108.17869643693));
#616=CARTESIAN_POINT('',(400.,81.0358907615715,107.443629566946));
#617=CARTESIAN_POINT('',(400.,85.7129435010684,106.023784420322));
#618=CARTESIAN_POINT('',(400.,88.0407588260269,105.338442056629));
#619=CARTESIAN_POINT('',(400.,92.7088043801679,104.011355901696));
#620=CARTESIAN_POINT('',(400.,95.0490345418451,103.369611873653));
#621=CARTESIAN_POINT('',(400.,99.7419023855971,102.134990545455));
#622=CARTESIAN_POINT('',(400.,102.094537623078,101.542103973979));
#623=CARTESIAN_POINT('',(400.,106.812415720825,100.411074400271));
#624=CARTESIAN_POINT('',(400.,109.177655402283,99.8729182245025));
#625=CARTESIAN_POINT('',(400.,112.73520340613,99.1117488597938));
#626=CARTESIAN_POINT('',(400.,113.922613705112,98.8657132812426));
#627=CARTESIAN_POINT('',(400.,116.300732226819,98.3900557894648));
#628=CARTESIAN_POINT('',(400.,117.491440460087,98.1604339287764));
#629=CARTESIAN_POINT('',(400.,119.876482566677,97.7187396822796));
#630=CARTESIAN_POINT('',(400.,121.070817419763,97.5066725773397));
#631=CARTESIAN_POINT('',(400.,123.462688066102,97.1015046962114));
#632=CARTESIAN_POINT('',(400.,124.660223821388,96.9084036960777));
#633=CARTESIAN_POINT('',(400.,127.507880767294,96.4740973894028));
#634=CARTESIAN_POINT('',(400.,129.159401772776,96.2419896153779));
#635=CARTESIAN_POINT('',(400.,132.468135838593,95.8207923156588));
#636=CARTESIAN_POINT('',(400.,134.125349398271,95.6317066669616));
#637=CARTESIAN_POINT('',(400.,136.614465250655,95.384305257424));
#638=CARTESIAN_POINT('',(400.,137.444591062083,95.3078849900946));
#639=CARTESIAN_POINT('',(400.,139.105927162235,95.1678332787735));
#640=CARTESIAN_POINT('',(400.,139.937137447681,95.1042017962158));
#641=CARTESIAN_POINT('',(400.,141.600083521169,94.9905818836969));
#642=CARTESIAN_POINT('',(400.,142.43181885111,94.9405867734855));
#643=CARTESIAN_POINT('',(400.,144.096028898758,94.8549114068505));
#644=CARTESIAN_POINT('',(400.,144.928503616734,94.8192311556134));
#645=CARTESIAN_POINT('',(400.,146.593606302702,94.7621970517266));
#646=CARTESIAN_POINT('',(400.,147.426234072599,94.7408374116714));
#647=CARTESIAN_POINT('',(400.,149.091734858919,94.7124646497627));
#648=CARTESIAN_POINT('',(400.,149.924607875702,94.7054515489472));
#649=CARTESIAN_POINT('',(400.,151.590123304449,94.705747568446));
#650=CARTESIAN_POINT('',(400.,152.422765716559,94.7130527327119));
#651=CARTESIAN_POINT('',(400.,154.087793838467,94.7419064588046));
#652=CARTESIAN_POINT('',(400.,154.920179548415,94.7634550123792));
#653=CARTESIAN_POINT('',(400.,157.432640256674,94.8498576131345));
#654=CARTESIAN_POINT('',(400.,159.112017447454,94.9364646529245));
#655=CARTESIAN_POINT('',(400.,162.467730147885,95.1657770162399));
#656=CARTESIAN_POINT('',(400.,164.144063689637,95.3085106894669));
#657=CARTESIAN_POINT('',(400.,167.492181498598,95.6476599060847));
#658=CARTESIAN_POINT('',(400.,169.16396284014,95.8441042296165));
#659=CARTESIAN_POINT('',(400.,172.50152288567,96.2873800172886));
#660=CARTESIAN_POINT('',(400.,174.167298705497,96.5342330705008));
#661=CARTESIAN_POINT('',(400.,177.491527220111,97.0741621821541));
#662=CARTESIAN_POINT('',(400.,179.149978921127,97.3672443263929));
#663=CARTESIAN_POINT('',(400.,182.458344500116,97.9946518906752));
#664=CARTESIAN_POINT('',(400.,184.10826147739,98.3289610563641));
#665=CARTESIAN_POINT('',(400.,187.381875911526,99.0295687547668));
#666=CARTESIAN_POINT('',(400.,189.005659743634,99.3954659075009));
#667=CARTESIAN_POINT('',(400.,192.246311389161,100.156794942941));
#668=CARTESIAN_POINT('',(400.,193.863178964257,100.552227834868));
#669=CARTESIAN_POINT('',(400.,197.090140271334,101.366511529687));
#670=CARTESIAN_POINT('',(400.,198.700236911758,101.785350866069));
#671=CARTESIAN_POINT('',(400.,201.91577843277,102.640558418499));
#672=CARTESIAN_POINT('',(400.,203.521223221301,103.076926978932));
#673=CARTESIAN_POINT('',(400.,206.729137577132,103.961089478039));
#674=CARTESIAN_POINT('',(400.,208.331606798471,104.408884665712));
#675=CARTESIAN_POINT('',(400.,211.535051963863,105.309721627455));
#676=CARTESIAN_POINT('',(400.,213.136027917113,105.762763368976));
#677=CARTESIAN_POINT('',(400.,216.338296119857,106.668085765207));
#678=CARTESIAN_POINT('',(400.,217.939588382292,107.120366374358));
#679=CARTESIAN_POINT('',(400.,221.144046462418,108.018263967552));
#680=CARTESIAN_POINT('',(400.,222.747212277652,108.463880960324));
#681=CARTESIAN_POINT('',(400.,225.956984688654,109.342816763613));
#682=CARTESIAN_POINT('',(400.,227.563591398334,109.776135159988));
#683=CARTESIAN_POINT('',(400.,230.781488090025,110.625094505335));
#684=CARTESIAN_POINT('',(400.,232.392778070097,111.040735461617));
#685=CARTESIAN_POINT('',(400.,235.622066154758,111.849574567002));
#686=CARTESIAN_POINT('',(400.,237.24006779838,112.242758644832));
#687=CARTESIAN_POINT('',(400.,240.482493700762,113.00178577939));
#688=CARTESIAN_POINT('',(400.,242.106917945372,113.36762889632));
#689=CARTESIAN_POINT('',(400.,245.331276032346,114.061091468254));
#690=CARTESIAN_POINT('',(400.,246.931080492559,114.389310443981));
#691=CARTESIAN_POINT('',(400.,250.137262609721,115.012012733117));
#692=CARTESIAN_POINT('',(400.,251.74364026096,115.30649607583));
#693=CARTESIAN_POINT('',(400.,254.964465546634,115.859098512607));
#694=CARTESIAN_POINT('',(400.,256.578920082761,116.117177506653));
#695=CARTESIAN_POINT('',(400.,259.813618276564,116.594186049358));
#696=CARTESIAN_POINT('',(400.,261.433861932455,116.813115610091));
#697=CARTESIAN_POINT('',(400.,264.679402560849,117.209972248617));
#698=CARTESIAN_POINT('',(400.,266.304699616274,117.387898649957));
#699=CARTESIAN_POINT('',(400.,269.559379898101,117.701428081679));
#700=CARTESIAN_POINT('',(400.,271.188763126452,117.837031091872));
#701=CARTESIAN_POINT('',(400.,274.449954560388,118.065073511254));
#702=CARTESIAN_POINT('',(400.,276.081761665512,118.157528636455));
#703=CARTESIAN_POINT('',(400.,279.347255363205,118.299031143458));
#704=CARTESIAN_POINT('',(400.,280.980941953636,118.348078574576));
#705=CARTESIAN_POINT('',(400.,284.248139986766,118.402866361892));
#706=CARTESIAN_POINT('',(400.,285.881651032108,118.408630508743));
#707=CARTESIAN_POINT('',(400.,289.148268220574,118.377406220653));
#708=CARTESIAN_POINT('',(400.,290.781374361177,118.340417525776));
#709=CARTESIAN_POINT('',(400.,294.044572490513,118.224549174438));
#710=CARTESIAN_POINT('',(400.,295.674665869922,118.145708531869));
#711=CARTESIAN_POINT('',(400.,298.932315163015,117.947227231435));
#712=CARTESIAN_POINT('',(400.,300.559871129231,117.827587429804));
#713=CARTESIAN_POINT('',(400.,304.199242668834,117.51552260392));
#714=CARTESIAN_POINT('',(400.,306.210158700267,117.312545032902));
#715=CARTESIAN_POINT('',(400.,310.225069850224,116.848659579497));
#716=CARTESIAN_POINT('',(400.,312.229065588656,116.587757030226));
#717=CARTESIAN_POINT('',(400.,316.229463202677,116.010870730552));
#718=CARTESIAN_POINT('',(400.,318.225863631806,115.694876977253));
#719=CARTESIAN_POINT('',(400.,322.210390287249,115.010735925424));
#720=CARTESIAN_POINT('',(400.,324.198513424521,114.642570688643));
#721=CARTESIAN_POINT('',(400.,328.165818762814,113.857041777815));
#722=CARTESIAN_POINT('',(400.,330.144997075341,113.439658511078));
#723=CARTESIAN_POINT('',(400.,334.0937398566,112.558639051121));
#724=CARTESIAN_POINT('',(400.,336.06330069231,112.094986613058));
#725=CARTESIAN_POINT('',(400.,340.122567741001,111.092112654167));
#726=CARTESIAN_POINT('',(400.,342.211537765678,110.549914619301));
#727=CARTESIAN_POINT('',(400.,346.376839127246,109.419715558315));
#728=CARTESIAN_POINT('',(400.,348.453171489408,108.831718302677));
#729=CARTESIAN_POINT('',(400.,352.592208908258,107.613338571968));
#730=CARTESIAN_POINT('',(400.,354.654920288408,106.982977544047));
#731=CARTESIAN_POINT('',(400.,358.765696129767,105.683202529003));
#732=CARTESIAN_POINT('',(400.,360.813773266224,105.01382857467));
#733=CARTESIAN_POINT('',(400.,364.894229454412,103.639285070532));
#734=CARTESIAN_POINT('',(400.,366.926628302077,102.934174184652));
#735=CARTESIAN_POINT('',(400.,370.97466244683,101.491272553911));
#736=CARTESIAN_POINT('',(400.,372.990325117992,100.753558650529));
#737=CARTESIAN_POINT('',(400.,375.,100.));
#738=B_SPLINE_CURVE_WITH_KNOTS('',3,(#448,#449,#450,#451,#452,#453,#454,#455,#456,#457,#458,
#459,#460,#461,#462,#463,#464,#465,#466,#467,#468,#469,#470,#471,#472,#473,#474,#475,#476,#477,
#478,#479,#480,#481,#482,#483,#484,#485,#486,#487,#488,#489,#490,#491,#492,#493,#494,#495,#496,
#497,#498,#499,#500,#501,#502,#503,#504,#505,#506,#507,#508,#509,#510,#511,#512,#513,#514,#515,
#516,#517,#518,#519,#520,#521,#522,#523,#524,#525,#526,#527,#528,#529,#530,#531,#532,#533,#534,
#535,#536,#537,#538,#539,#540,#541,#542,#543,#544,#545,#546,#547,#548,#549,#550,#551,#552,#553,
#554,#555,#556,#557,#558,#559,#560,#561,#562,#563,#564,#565,#566,#567,#568,#569,#570,#571,#572,
#573,#574,#575,#576,#577,#578,#579,#580,#581,#582,#583,#584,#585,#586,#587,#588,#589,#590,#591,
#592,#593,#594,#595,#596,#597,#598,#599,#600,#601,#602,#603,#604,#605,#606,#607,#608,#609,#610,
#611,#612,#613,#614,#615,#616,#617,#618,#619,#620,#621,#622,#623,#624,#625,#626,#627,#628,#629,
#630,#631,#632,#633,#634,#635,#636,#637,#638,#639,#640,#641,#642,#643,#644,#645,#646,#647,#648,
#649,#650,#651,#652,#653,#654,#655,#656,#657,#658,#659,#660,#661,#662,#663,#664,#665,#666,#667,
#668,#669,#670,#671,#672,#673,#674,#675,#676,#677,#678,#679,#680,#681,#682,#683,#684,#685,#686,
#687,#688,#689,#690,#691,#692,#693,#694,#695,#696,#697,#698,#699,#700,#701,#702,#703,#704,#705,
#706,#707,#708,#709,#710,#711,#712,#713,#714,#715,#716,#717,#718,#719,#720,#721,#722,#723,#724,
#725,#726,#727,#728,#729,#730,#731,#732,#733,#734,#735,#736,#737),.UNSPECIFIED.,.F.,.F.,(4,2,2,
2,2,2,2,2,2,2,2,2,2,2,2,2,2,2,2,2,2,2,2,2,2,2,2,2,2,2,2,2,2,2,2,2,2,2,2,2,2,2,2,2,2,2,2,2,2,2,2,
2,2,2,2,2,2,2,2,2,2,2,2,2,2,2,2,2,2,2,2,2,2,2,2,2,2,2,2,2,2,2,2,2,2,2,2,2,2,2,2,2,2,2,2,2,2,2,2,
2,2,2,2,2,2,2,2,2,2,2,2,2,2,2,2,2,2,2,2,2,2,2,2,2,2,2,2,2,2,2,2,2,2,2,2,2,2,2,2,2,2,2,2,2,4),
(0.,6.17605059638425,12.3528494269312,18.5297723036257,24.7064959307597,30.882941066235,
37.0592042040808,43.0716993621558,49.0837688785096,55.0954702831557,61.1068337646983,
67.117769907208,73.1279747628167,78.4034960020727,83.6791607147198,88.9560003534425,
94.2328795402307,99.5114124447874,104.789955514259,110.068285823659,115.346725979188,
120.719532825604,126.092449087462,131.463927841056,136.835352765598,142.205599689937,
147.575832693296,152.942679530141,158.309527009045,165.437255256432,172.562855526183,
179.690349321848,186.823799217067,193.967757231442,201.12791247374,208.079443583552,
215.03409177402,221.97883155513,228.906111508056,232.361363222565,235.816414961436,
239.267693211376,242.718679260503,244.42667505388,246.134633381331,247.843765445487,
249.552905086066,251.262894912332,252.972886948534,256.394022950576,259.815576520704,
263.236077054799,266.695351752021,270.154070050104,273.612775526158,277.071466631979,
280.529633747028,283.986300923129,290.567029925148,297.148886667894,303.733476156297,
310.317744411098,316.920340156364,323.523008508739,330.143751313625,336.764466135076,
343.395228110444,350.025992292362,356.65475946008,363.283522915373,370.010907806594,
376.738292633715,383.451003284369,390.163712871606,396.865537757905,403.56736317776,
416.956924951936,430.340826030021,443.728732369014,451.100480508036,458.475655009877,
465.853408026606,473.233198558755,480.614862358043,487.998704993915,495.278146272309,
502.557548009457,509.835565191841,517.111826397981,520.749628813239,524.387442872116,
528.026347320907,531.665208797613,536.667959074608,541.671160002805,544.171986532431,
546.672805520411,549.172397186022,551.67198975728,554.170571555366,556.669157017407,
559.167052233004,561.664946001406,566.708712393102,571.7550296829,576.804056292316,
581.855249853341,586.907108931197,591.956982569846,596.950148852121,601.943485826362,
606.934397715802,611.925407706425,616.916965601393,621.908492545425,626.900308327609,
631.892117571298,636.884094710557,641.876069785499,646.871139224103,651.866197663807,
656.765249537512,661.664297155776,666.568699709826,671.473100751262,676.377582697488,
681.282066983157,686.184763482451,691.087454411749,695.987450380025,700.887476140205,
705.782942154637,710.678305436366,716.740793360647,722.80272334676,728.865755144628,
734.930876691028,740.998420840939,747.068102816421,753.542100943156,760.015566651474,
766.485779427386,772.949465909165,779.40286546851,785.841791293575),.UNSPECIFIED.);
#739=CARTESIAN_POINT('',(400.,-375.,100.));
#740=VERTEX_POINT('',#739);
#741=CARTESIAN_POINT('',(400.,375.,100.));
#742=VERTEX_POINT('',#741);
#743=EDGE_CURVE('E11',#740,#742,#738,.T.);
#744=CARTESIAN_POINT('',(-750.,-375.,100.));
#745=CARTESIAN_POINT('',(-644.685568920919,-375.,100.));
#746=CARTESIAN_POINT('',(-536.684515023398,-375.,100.));
#747=CARTESIAN_POINT('',(-355.235514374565,-375.,100.));
#748=CARTESIAN_POINT('',(-175.903454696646,-375.,100.));
#749=CARTESIAN_POINT('',(47.4554331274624,-375.,100.));
#750=CARTESIAN_POINT('',(285.091607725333,-375.,100.));
#751=CARTESIAN_POINT('',(500.445116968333,-375.,100.));
#752=CARTESIAN_POINT('',(669.085175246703,-375.,100.));
#753=CARTESIAN_POINT('',(750.,-375.,100.));
#754=B_SPLINE_CURVE_WITH_KNOTS('',3,(#744,#745,#746,#747,#748,#749,#750,#751,#752,#753),
.UNSPECIFIED.,.F.,.F.,(4,1,1,1,1,1,1,4),(0.,0.210628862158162,0.216002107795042,
0.362898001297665,0.569292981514,0.66271988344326,0.838170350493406,1.),.UNSPECIFIED.);
#755=EDGE_CURVE('E97',#740,#308,#754,.T.);
#756=CARTESIAN_POINT('',(750.,375.,100.));
#757=CARTESIAN_POINT('',(669.085175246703,375.,100.));
#758=CARTESIAN_POINT('',(500.445116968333,375.,100.));
#759=CARTESIAN_POINT('',(285.091607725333,375.,100.));
#760=CARTESIAN_POINT('',(47.4554331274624,375.,100.));
#761=CARTESIAN_POINT('',(-175.903454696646,375.,100.));
#762=CARTESIAN_POINT('',(-355.235514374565,375.,100.));
#763=CARTESIAN_POINT('',(-536.684515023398,375.,100.));
#764=CARTESIAN_POINT('',(-644.685568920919,375.,100.));
#765=CARTESIAN_POINT('',(-750.,375.,100.));
#766=B_SPLINE_CURVE_WITH_KNOTS('',3,(#756,#757,#758,#759,#760,#761,#762,#763,#764,#765),
.UNSPECIFIED.,.F.,.F.,(4,1,1,1,1,1,1,4),(0.,0.161829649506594,0.33728011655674,0.430707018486,
0.637101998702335,0.783997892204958,0.789371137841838,1.),.UNSPECIFIED.);
#767=EDGE_CURVE('E94',#306,#742,#766,.T.);
#768=ORIENTED_EDGE('',*,*,#743,.F.);
#769=ORIENTED_EDGE('',*,*,#755,.T.);
#770=ORIENTED_EDGE('',*,*,#309,.F.);
#771=ORIENTED_EDGE('',*,*,#767,.T.);
#772=EDGE_LOOP('',(#768,#769,#770,#771));
#773=FACE_BOUND('',#772,.T.);
#774=ADVANCED_FACE('F110',(#773),#447,.F.);
#775=CARTESIAN_POINT('',(-750.,375.,253.111113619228));
#776=DIRECTION('',(0.,-1.,0.));
#777=DIRECTION('',(0.,0.,-1.));
#778=AXIS2_PLACEMENT_3D('',#775,#776,#777);
#779=PLANE('',#778);
#780=DIRECTION('',(0.,0.,-1.));
#781=VECTOR('',#780,1.);
#782=CARTESIAN_POINT('',(400.,375.,253.120113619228));
#783=LINE('',#782,#781);
#784=EDGE_CURVE('E154',#742,#354,#783,.T.);
#785=ORIENTED_EDGE('',*,*,#784,.F.);
#786=ORIENTED_EDGE('',*,*,#767,.F.);
#787=ORIENTED_EDGE('',*,*,#331,.T.);
#788=ORIENTED_EDGE('',*,*,#361,.T.);
#789=EDGE_LOOP('',(#785,#786,#787,#788));
#790=FACE_BOUND('',#789,.T.);
#791=ADVANCED_FACE('F121',(#790),#779,.F.);
#792=CARTESIAN_POINT('',(-750.,-375.,253.111113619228));
#793=DIRECTION('',(0.,1.,0.));
#794=DIRECTION('',(0.,0.,1.));
#795=AXIS2_PLACEMENT_3D('',#792,#793,#794);
#796=PLANE('',#795);
#797=DIRECTION('',(0.,0.,-1.));
#798=VECTOR('',#797,1.);
#799=CARTESIAN_POINT('',(400.,-375.,253.120113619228));
#800=LINE('',#799,#798);
#801=EDGE_CURVE('E56',#740,#346,#800,.T.);
#802=ORIENTED_EDGE('',*,*,#801,.T.);
#803=ORIENTED_EDGE('',*,*,#347,.T.);
#804=ORIENTED_EDGE('',*,*,#317,.F.);
#805=ORIENTED_EDGE('',*,*,#755,.F.);
#806=EDGE_LOOP('',(#802,#803,#804,#805));
#807=FACE_BOUND('',#806,.T.);
#808=ADVANCED_FACE('F37',(#807),#796,.F.);
#809=CARTESIAN_POINT('',(400.,375.,253.120113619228));
#810=DIRECTION('',(-1.,0.,0.));
#811=DIRECTION('',(0.,-1.,0.));
#812=AXIS2_PLACEMENT_3D('',#809,#810,#811);
#813=PLANE('',#812);
#814=ORIENTED_EDGE('',*,*,#743,.T.);
#815=ORIENTED_EDGE('',*,*,#784,.T.);
#816=ORIENTED_EDGE('',*,*,#355,.F.);
#817=ORIENTED_EDGE('',*,*,#801,.F.);
#818=EDGE_LOOP('',(#814,#815,#816,#817));
#819=FACE_BOUND('',#818,.T.);
#820=ADVANCED_FACE('F145',(#819),#813,.T.);
#821=CLOSED_SHELL('',(#335,#366,#774,#791,#808,#820));
#822=MANIFOLD_SOLID_BREP('B2',#821);
#823=ADVANCED_BREP_SHAPE_REPRESENTATION('',(#18,#822),#14);
#824=SHAPE_DEFINITION_REPRESENTATION(#9,#823);
ENDSEC;
END-ISO-10303-21;
